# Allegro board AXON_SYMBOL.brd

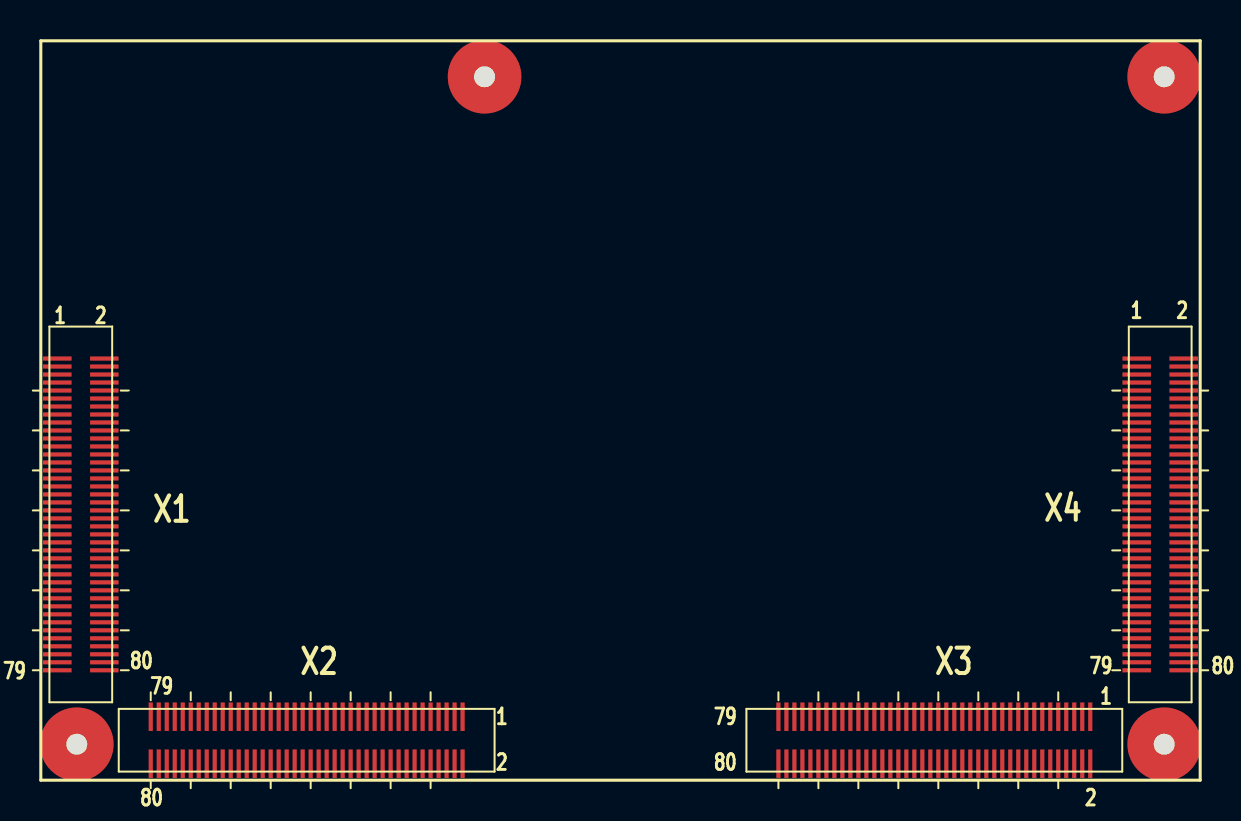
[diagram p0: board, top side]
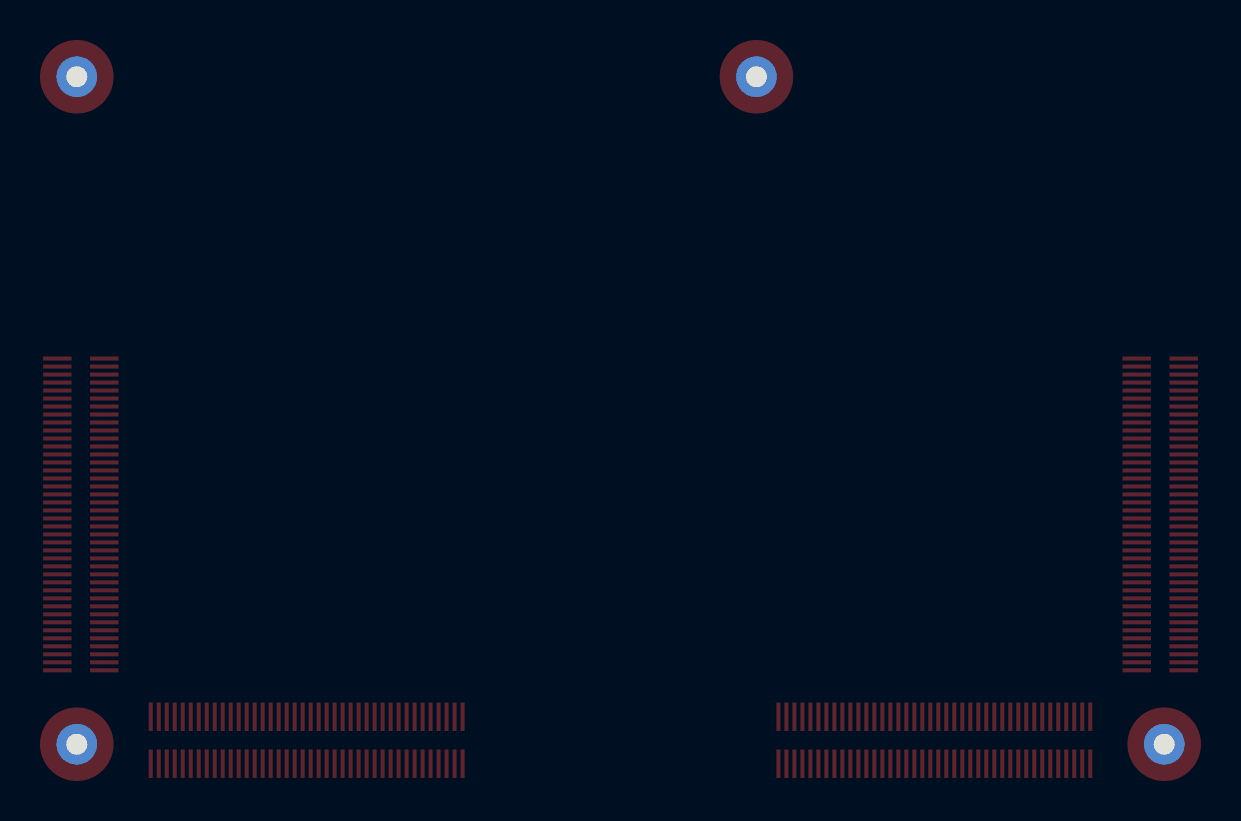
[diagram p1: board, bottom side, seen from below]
No outline. copper layers: TOP, GND, VCC, IN1, GND1, BOTTOM. Coordinates in mm from the lowest, leftmost part position.

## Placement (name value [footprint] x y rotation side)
HOLE1  HOLE-X  [MCT145B80D41_PAST]  89.24 59.47 0 top
HOLE2  HOLE-X  [MCT145B80D41_PAST]  34.84 59.47 0 top
HOLE3  HOLE-X  [MCT145B80D41_PAST]  55.24 92.87 0 top
HOLE4  HOLE-X  [MCT145B80D41_PAST]  89.24 92.87 270 top
NOREF  -  []  0 133.45 270 top
NOREF#2  -  []  51.16 0 0 top
NOREF#3  -  []  2.01 7.42 180 bottom
X1  DF40HC(4.0)-80DS-0.4V(51)  [DF40HC-80DS-0D4V_LD_H4]  35.04 70.97 270 top
X2  DF40HC(4.0)-80DS-0.4V(51)  [DF40HC-80DS-0D4V_LD_H4]  46.34 59.67 180 top
X3  DF40HC(4.0)-80DS-0.4V(51)  [DF40HC-80DS-0D4V_LD_H4]  77.74 59.67 180 top
X4  DF40HC(4.0)-80DS-0.4V(51)  [DF40HC-80DS-0D4V_LD_H4]  89.04 70.97 270 top

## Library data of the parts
HOLE1-HOLE4 = MCT145B80D41_PAST
X1-X4 = DF40HC-80DS-0D4V_LD_H4

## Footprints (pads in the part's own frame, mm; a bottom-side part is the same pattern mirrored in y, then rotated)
DF40HC-80DS-0D4V_LD_H4
  rect 0.203x1.422 smd: 1(-7.8,-1.175) 2(-7.8,1.175) 3(-7.4,-1.175) 4(-7.4,1.175) 5(-7,-1.175) 6(-7,1.175) 7(-6.6,-1.175) 8(-6.6,1.175) 9(-6.2,-1.175) 10(-6.2,1.175) 11(-5.8,-1.175) 12(-5.8,1.175) 13(-5.4,-1.175) 14(-5.4,1.175) 15(-5,-1.175) 16(-5,1.175) 17(-4.6,-1.175) 18(-4.6,1.175) 19(-4.2,-1.175) 20(-4.2,1.175) 21(-3.8,-1.175) 22(-3.8,1.175) 23(-3.4,-1.175) 24(-3.4,1.175) 25(-3,-1.175) 26(-3,1.175) 27(-2.6,-1.175) 28(-2.6,1.175) 29(-2.2,-1.175) 30(-2.2,1.175) 31(-1.8,-1.175) 32(-1.8,1.175) 33(-1.4,-1.175) 34(-1.4,1.175) 35(-1,-1.175) 36(-1,1.175) 37(-0.6,-1.175) 38(-0.6,1.175) 39(-0.2,-1.175) 40(-0.2,1.175) 41(0.2,-1.175) 42(0.2,1.175) 43(0.6,-1.175) 44(0.6,1.175) 45(1,-1.175) 46(1,1.175) 47(1.4,-1.175) 48(1.4,1.175) 49(1.8,-1.175) 50(1.8,1.175) 51(2.2,-1.175) 52(2.2,1.175) 53(2.6,-1.175) 54(2.6,1.175) 55(3,-1.175) 56(3,1.175) 57(3.4,-1.175) 58(3.4,1.175) 59(3.8,-1.175) 60(3.8,1.175) 61(4.2,-1.175) 62(4.2,1.175) 63(4.6,-1.175) 64(4.6,1.175) 65(5,-1.175) 66(5,1.175) 67(5.4,-1.175) 68(5.4,1.175) 69(5.8,-1.175) 70(5.8,1.175) 71(6.2,-1.175) 72(6.2,1.175) 73(6.6,-1.175) 74(6.6,1.175) 75(7,-1.175) 76(7,1.175) 77(7.4,-1.175) 78(7.4,1.175) 79(7.8,-1.175) 80(7.8,1.175)
MCT145B80D41_PAST
  round 3.683 hole 1.041: 1(0,0)

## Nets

Pads without a net: HOLE1 1; HOLE2 1; HOLE3 1; HOLE4 1; X1 1 2 3 4 5 6 7 8 9 10 11 12 13 14 15 16 17 18 19 20 21 22 23 24 25 26 27 28 29 30 31 32 33 34 35 36 37 38 39 40 41 42 43 44 45 46 47 48 49 50 51 52 53 54 55 56 57 58 59 60 61 62 63 64 65 66 67 68 69 70 71 72 73 74 75 76 77 78 79 80; X2 1 2 3 4 5 6 7 8 9 10 11 12 13 14 15 16 17 18 19 20 21 22 23 24 25 26 27 28 29 30 31 32 33 34 35 36 37 38 39 40 41 42 43 44 45 46 47 48 49 50 51 52 53 54 55 56 57 58 59 60 61 62 63 64 65 66 67 68 69 70 71 72 73 74 75 76 77 78 79 80; X3 1 2 3 4 5 6 7 8 9 10 11 12 13 14 15 16 17 18 19 20 21 22 23 24 25 26 27 28 29 30 31 32 33 34 35 36 37 38 39 40 41 42 43 44 45 46 47 48 49 50 51 52 53 54 55 56 57 58 59 60 61 62 63 64 65 66 67 68 69 70 71 72 73 74 75 76 77 78 79 80; X4 1 2 3 4 5 6 7 8 9 10 11 12 13 14 15 16 17 18 19 20 21 22 23 24 25 26 27 28 29 30 31 32 33 34 35 36 37 38 39 40 41 42 43 44 45 46 47 48 49 50 51 52 53 54 55 56 57 58 59 60 61 62 63 64 65 66 67 68 69 70 71 72 73 74 75 76 77 78 79 80

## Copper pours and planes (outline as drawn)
Net_7 on GND: 65.63,8.56 65.63,18.61 66.25,19.23 68.96,19.23 69.19,19 69.19,15.95 69.72,15.42 80.22,15.42 80.75,15.95 80.75,19.25 80.85,19.35 83.44,19.35 83.54,19.25 83.54,8.56
Net_8 on GND1: 65.63,8.56 65.63,18.61 66.25,19.23 68.96,19.23 69.19,19 69.19,15.95 69.72,15.42 80.22,15.42 80.75,15.95 80.75,19.25 80.85,19.35 83.44,19.35 83.54,19.25 83.54,8.56
Net_10 on VCC: 65.63,8.56 65.63,18.61 66.25,19.23 68.96,19.23 69.19,19 69.19,15.95 69.72,15.42 80.22,15.42 80.75,15.95 80.75,19.25 80.85,19.35 83.44,19.35 83.54,19.25 83.54,8.56
Net_97 on VCC: outline of 131 points within 14.52,14.15 158.79,158.23 ; 1 cut-out
Net_194 on VCC: 84.05,8.56 84.05,13.64 88.13,13.64 88.87,12.9 88.87,11.5 89.4,10.97 92.79,10.97 93.19,11.38 93.19,14.02 100.33,14.02 100.56,13.79 100.56,11.63 100.96,11.23 107.39,11.23 107.92,11.76 107.92,13.64 129.39,13.64 129.39,8.56
Net_265 on GND: 3.36,8.56 3.02,8.9 3.02,175.86 3.49,176.33 170.33,176.33 170.92,175.74 170.92,9.02 170.45,8.56 149.58,8.56 149.58,24.18 149.45,24.31 144.65,24.31 143.87,23.52 143.87,21.49 143.61,21.24 143.61,17.68 143,17.07 134.57,17.07 134.34,17.3 134.34,20.22 134.09,20.48 134.09,23.78 133.56,24.31 129.92,24.31 129.39,23.78 129.39,8.56 84.05,8.56 84.05,19.46 83.65,19.86 80.64,19.86 80.24,19.46 80.24,16.16 80.01,15.93 69.93,15.93 69.7,16.16 69.7,19.21 69.17,19.74 66.04,19.74 65.13,18.82 65.13,8.56
Net_266 on GND1: 3.36,8.56 3.02,8.9 3.02,175.86 3.49,176.33 170.33,176.33 170.92,175.74 170.92,9.02 170.45,8.56 149.58,8.56 149.58,24.16 149.43,24.31 144.65,24.31 143.87,23.52 143.87,21.49 143.61,21.24 143.61,17.68 143,17.07 134.57,17.07 134.34,17.3 134.34,20.22 134.09,20.48 134.09,23.78 133.56,24.31 129.92,24.31 129.39,23.78 129.39,8.56 84.05,8.56 84.05,19.46 83.65,19.86 80.64,19.86 80.24,19.46 80.24,16.16 80.01,15.93 69.93,15.93 69.7,16.16 69.7,19.21 69.17,19.74 66.04,19.74 65.13,18.82 65.13,8.56
Net_268 on VCC: 3.36,8.56 3.02,8.9 3.02,175.86 3.49,176.33 170.33,176.33 170.92,175.74 170.92,9.02 170.45,8.56 149.58,8.56 149.58,28.09 147.52,30.15 140.28,30.15 139.8,30.63 139.8,39.07 140.16,39.42 153.54,39.42 153.64,39.32 153.64,37.9 153.64,37.9 153.64,37.29 154.17,36.75 154.26,36.75 154.33,36.69 155.37,36.69 155.74,37.06 155.74,37.44 155.88,37.58 158.93,37.58 159.17,37.82 159.17,38.71 159.25,38.79 159.25,38.79 165.84,38.79 166.47,39.42 166.47,79.22 166.65,79.4 169.88,79.4 170.13,79.65 170.13,84.43 169.06,85.5 166.73,85.5 166.47,85.75 166.47,98.07 165.46,99.09 165.46,157.51 163.78,159.18 141.3,159.18 140.31,160.18 140.31,168.43 138,170.74 83.39,170.74 81.23,172.9 19.05,172.9 14.73,168.58 6.22,168.58 4.29,166.65 4.29,15.06 5.58,13.77 20.91,13.77 23.22,16.07 23.22,20.77 24.59,22.15 64.26,22.15 65.89,20.52 65.89,19.59 65.13,18.82 65.13,8.56
Net_489 on VCC: 80.43,157.72 80.43,161.52 81.21,162.29 93.62,162.29 94.26,161.66 95.43,161.66 96.19,162.42 99.08,162.42 99.48,162.02 99.48,158.5 98.7,157.72 96.49,157.72 95.61,158.61 87.14,158.61 86.51,157.98 83.72,157.98 83.46,157.72
Net_548 on VCC: 78.03,120 73.08,124.96 69.11,124.96 67.71,123.56 65.84,123.56 64.94,124.46 64.94,125.48 64.06,126.35 54.79,126.35 52.89,128.26 44.11,128.26 43.03,129.34 43.03,133.77 46.15,136.89 89.56,136.89 97.43,129.02 104.92,129.02 105.96,127.99 105.96,121.67 104.29,120
Net_578 on VCC: outline of 208 points within 4.8,11.48 165.96,172.39
Net_594 on GND: 129.9,8.56 129.9,23.57 130.13,23.8 133.35,23.8 133.58,23.57 133.58,20.27 133.83,20.01 133.83,17.09 134.36,16.56 143.21,16.56 144.12,17.47 144.12,21.03 144.37,21.28 144.37,23.31 144.86,23.8 149.07,23.8 149.07,8.56
Net_595 on GND1: 129.9,8.56 129.9,23.57 130.13,23.8 133.35,23.8 133.58,23.57 133.58,20.27 133.83,20.01 133.83,17.09 134.36,16.56 143.21,16.56 144.12,17.47 144.12,21.03 144.37,21.28 144.37,23.31 144.86,23.8 149.07,23.8 149.07,8.56
Net_597 on VCC: 129.9,8.56 129.9,23.57 130.13,23.8 133.35,23.8 133.58,23.57 133.58,20.27 133.83,20.01 133.83,17.09 134.36,16.56 143.21,16.56 144.12,17.47 144.12,21.03 144.37,21.28 144.37,23.31 144.86,23.8 149.07,23.8 149.07,8.56
Net_611 on VCC: 161.59,84.4 165.81,84.4 166.42,85.01 168.91,85.01 169.65,84.28 169.65,82.75 169.21,82.32 167.89,82.32 166.78,83.44 163.86,83.44 163.86,83.36 162.79,82.3 161.52,82.3 161.26,82.55 161.26,84.07
Net_619 on VCC: 164.03,83.06 166.6,83.06 167.79,81.86 169.47,81.86 169.67,81.66 169.67,80.09 169.49,79.91 163.78,79.91 162.99,80.7 162.99,82.02

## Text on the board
BOTTOM: 01
Ref Des/Silkscreen Bottom: 02 | CLIX SLOT
IN1: LAYER4  IN1
GND1: LAYER5  GND1
BODY_CENTER: C1=anti/sha/dr/nc/art: Nov 30 13:41:51 2020 ; 0/0/1/0/0
User.13: FIGURE | SIZE | 8.0 | 10.0 | 12.0 | 14.0 | 16.0 | 20.0 | 28.0 | 29.0 | 32.0 | 36.0 | 40.0 | 41.0 | 47.0 | 55.0 | 63.0 | 83.0 | 91.0 | 165.0 | 22.0 | 26.0 | 30.0 | 43.0 | 106.0 | 118.0 | 128.0 | 30x16 | 20x43 | 24x47 | 20x60 | 35x83 | 35x106 | 37x26 | DRILL CHART: TOP to BOTTOM | ALL UNITS ARE IN MILS | PLATED | NON-PLATED | QTY | 34 | 1480 | 605 | 377 | 12 | 322 | 82 | 7 | 2 | 20 | 16 | 1 | 4 | 6 | 5
